VERSION 5.7 ;
  NOWIREEXTENSIONATPIN ON ;
  DIVIDERCHAR "/" ;
  BUSBITCHARS "[]" ;
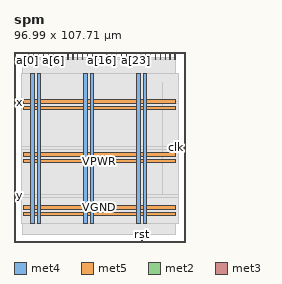
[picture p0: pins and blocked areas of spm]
MACRO spm
  CLASS BLOCK ;
  FOREIGN spm ;
  ORIGIN 0.000 0.000 ;
  SIZE 96.990 BY 107.710 ;
  PIN VGND
    DIRECTION INOUT ;
    USE GROUND ;
    PORT
      LAYER met4 ;
        RECT 13.220 10.640 15.220 95.440 ;
    END
    PORT
      LAYER met4 ;
        RECT 43.220 10.640 45.220 95.440 ;
    END
    PORT
      LAYER met4 ;
        RECT 73.220 10.640 75.220 95.440 ;
    END
    PORT
      LAYER met5 ;
        RECT 5.280 18.580 91.320 20.580 ;
    END
    PORT
      LAYER met5 ;
        RECT 5.280 48.580 91.320 50.580 ;
    END
    PORT
      LAYER met5 ;
        RECT 5.280 78.580 91.320 80.580 ;
    END
  END VGND
  PIN VPWR
    DIRECTION INOUT ;
    USE POWER ;
    PORT
      LAYER met4 ;
        RECT 9.520 10.640 11.520 95.440 ;
    END
    PORT
      LAYER met4 ;
        RECT 39.520 10.640 41.520 95.440 ;
    END
    PORT
      LAYER met4 ;
        RECT 69.520 10.640 71.520 95.440 ;
    END
    PORT
      LAYER met5 ;
        RECT 5.280 14.880 91.320 16.880 ;
    END
    PORT
      LAYER met5 ;
        RECT 5.280 44.880 91.320 46.880 ;
    END
    PORT
      LAYER met5 ;
        RECT 5.280 74.880 91.320 76.880 ;
    END
  END VPWR
  PIN a[0]
    DIRECTION INPUT ;
    USE SIGNAL ;
    ANTENNAGATEAREA 0.196500 ;
    PORT
      LAYER met2 ;
        RECT 5.610 103.710 5.890 107.710 ;
    END
  END a[0]
  PIN a[10]
    DIRECTION INPUT ;
    USE SIGNAL ;
    ANTENNAGATEAREA 0.196500 ;
    PORT
      LAYER met2 ;
        RECT 33.210 103.710 33.490 107.710 ;
    END
  END a[10]
  PIN a[11]
    DIRECTION INPUT ;
    USE SIGNAL ;
    ANTENNAGATEAREA 0.196500 ;
    PORT
      LAYER met2 ;
        RECT 35.970 103.710 36.250 107.710 ;
    END
  END a[11]
  PIN a[12]
    DIRECTION INPUT ;
    USE SIGNAL ;
    ANTENNAGATEAREA 0.196500 ;
    PORT
      LAYER met2 ;
        RECT 38.730 103.710 39.010 107.710 ;
    END
  END a[12]
  PIN a[13]
    DIRECTION INPUT ;
    USE SIGNAL ;
    ANTENNAGATEAREA 0.196500 ;
    PORT
      LAYER met2 ;
        RECT 41.490 103.710 41.770 107.710 ;
    END
  END a[13]
  PIN a[14]
    DIRECTION INPUT ;
    USE SIGNAL ;
    ANTENNAGATEAREA 0.196500 ;
    PORT
      LAYER met2 ;
        RECT 44.250 103.710 44.530 107.710 ;
    END
  END a[14]
  PIN a[15]
    DIRECTION INPUT ;
    USE SIGNAL ;
    ANTENNAGATEAREA 0.196500 ;
    PORT
      LAYER met2 ;
        RECT 47.010 103.710 47.290 107.710 ;
    END
  END a[15]
  PIN a[16]
    DIRECTION INPUT ;
    USE SIGNAL ;
    ANTENNAGATEAREA 0.196500 ;
    PORT
      LAYER met2 ;
        RECT 49.770 103.710 50.050 107.710 ;
    END
  END a[16]
  PIN a[17]
    DIRECTION INPUT ;
    USE SIGNAL ;
    ANTENNAGATEAREA 0.196500 ;
    PORT
      LAYER met2 ;
        RECT 52.530 103.710 52.810 107.710 ;
    END
  END a[17]
  PIN a[18]
    DIRECTION INPUT ;
    USE SIGNAL ;
    ANTENNAGATEAREA 0.196500 ;
    PORT
      LAYER met2 ;
        RECT 55.290 103.710 55.570 107.710 ;
    END
  END a[18]
  PIN a[19]
    DIRECTION INPUT ;
    USE SIGNAL ;
    ANTENNAGATEAREA 0.196500 ;
    PORT
      LAYER met2 ;
        RECT 58.050 103.710 58.330 107.710 ;
    END
  END a[19]
  PIN a[1]
    DIRECTION INPUT ;
    USE SIGNAL ;
    ANTENNAGATEAREA 0.196500 ;
    PORT
      LAYER met2 ;
        RECT 8.370 103.710 8.650 107.710 ;
    END
  END a[1]
  PIN a[20]
    DIRECTION INPUT ;
    USE SIGNAL ;
    ANTENNAGATEAREA 0.196500 ;
    PORT
      LAYER met2 ;
        RECT 60.810 103.710 61.090 107.710 ;
    END
  END a[20]
  PIN a[21]
    DIRECTION INPUT ;
    USE SIGNAL ;
    ANTENNAGATEAREA 0.196500 ;
    PORT
      LAYER met2 ;
        RECT 63.570 103.710 63.850 107.710 ;
    END
  END a[21]
  PIN a[22]
    DIRECTION INPUT ;
    USE SIGNAL ;
    ANTENNAGATEAREA 0.196500 ;
    PORT
      LAYER met2 ;
        RECT 66.330 103.710 66.610 107.710 ;
    END
  END a[22]
  PIN a[23]
    DIRECTION INPUT ;
    USE SIGNAL ;
    ANTENNAGATEAREA 0.196500 ;
    PORT
      LAYER met2 ;
        RECT 69.090 103.710 69.370 107.710 ;
    END
  END a[23]
  PIN a[24]
    DIRECTION INPUT ;
    USE SIGNAL ;
    ANTENNAGATEAREA 0.196500 ;
    PORT
      LAYER met2 ;
        RECT 71.850 103.710 72.130 107.710 ;
    END
  END a[24]
  PIN a[25]
    DIRECTION INPUT ;
    USE SIGNAL ;
    ANTENNAGATEAREA 0.196500 ;
    PORT
      LAYER met2 ;
        RECT 74.610 103.710 74.890 107.710 ;
    END
  END a[25]
  PIN a[26]
    DIRECTION INPUT ;
    USE SIGNAL ;
    ANTENNAGATEAREA 0.196500 ;
    PORT
      LAYER met2 ;
        RECT 77.370 103.710 77.650 107.710 ;
    END
  END a[26]
  PIN a[27]
    DIRECTION INPUT ;
    USE SIGNAL ;
    ANTENNAGATEAREA 0.196500 ;
    PORT
      LAYER met2 ;
        RECT 80.130 103.710 80.410 107.710 ;
    END
  END a[27]
  PIN a[28]
    DIRECTION INPUT ;
    USE SIGNAL ;
    ANTENNAGATEAREA 0.196500 ;
    PORT
      LAYER met2 ;
        RECT 82.890 103.710 83.170 107.710 ;
    END
  END a[28]
  PIN a[29]
    DIRECTION INPUT ;
    USE SIGNAL ;
    ANTENNAGATEAREA 0.196500 ;
    PORT
      LAYER met2 ;
        RECT 85.650 103.710 85.930 107.710 ;
    END
  END a[29]
  PIN a[2]
    DIRECTION INPUT ;
    USE SIGNAL ;
    ANTENNAGATEAREA 0.196500 ;
    PORT
      LAYER met2 ;
        RECT 11.130 103.710 11.410 107.710 ;
    END
  END a[2]
  PIN a[30]
    DIRECTION INPUT ;
    USE SIGNAL ;
    ANTENNAGATEAREA 0.196500 ;
    PORT
      LAYER met2 ;
        RECT 88.410 103.710 88.690 107.710 ;
    END
  END a[30]
  PIN a[31]
    DIRECTION INPUT ;
    USE SIGNAL ;
    ANTENNAGATEAREA 0.196500 ;
    PORT
      LAYER met2 ;
        RECT 91.170 103.710 91.450 107.710 ;
    END
  END a[31]
  PIN a[3]
    DIRECTION INPUT ;
    USE SIGNAL ;
    ANTENNAGATEAREA 0.196500 ;
    PORT
      LAYER met2 ;
        RECT 13.890 103.710 14.170 107.710 ;
    END
  END a[3]
  PIN a[4]
    DIRECTION INPUT ;
    USE SIGNAL ;
    ANTENNAGATEAREA 0.196500 ;
    PORT
      LAYER met2 ;
        RECT 16.650 103.710 16.930 107.710 ;
    END
  END a[4]
  PIN a[5]
    DIRECTION INPUT ;
    USE SIGNAL ;
    ANTENNAGATEAREA 0.196500 ;
    PORT
      LAYER met2 ;
        RECT 19.410 103.710 19.690 107.710 ;
    END
  END a[5]
  PIN a[6]
    DIRECTION INPUT ;
    USE SIGNAL ;
    ANTENNAGATEAREA 0.196500 ;
    PORT
      LAYER met2 ;
        RECT 22.170 103.710 22.450 107.710 ;
    END
  END a[6]
  PIN a[7]
    DIRECTION INPUT ;
    USE SIGNAL ;
    ANTENNAGATEAREA 0.196500 ;
    PORT
      LAYER met2 ;
        RECT 24.930 103.710 25.210 107.710 ;
    END
  END a[7]
  PIN a[8]
    DIRECTION INPUT ;
    USE SIGNAL ;
    ANTENNAGATEAREA 0.196500 ;
    PORT
      LAYER met2 ;
        RECT 27.690 103.710 27.970 107.710 ;
    END
  END a[8]
  PIN a[9]
    DIRECTION INPUT ;
    USE SIGNAL ;
    ANTENNAGATEAREA 0.196500 ;
    PORT
      LAYER met2 ;
        RECT 30.450 103.710 30.730 107.710 ;
    END
  END a[9]
  PIN clk
    DIRECTION INPUT ;
    USE SIGNAL ;
    ANTENNAGATEAREA 0.852000 ;
    PORT
      LAYER met3 ;
        RECT 92.990 53.080 96.990 53.680 ;
    END
  END clk
  PIN rst
    DIRECTION INPUT ;
    USE SIGNAL ;
    ANTENNAGATEAREA 0.990000 ;
    PORT
      LAYER met2 ;
        RECT 72.310 0.000 72.590 4.000 ;
    END
  END rst
  PIN x
    DIRECTION INPUT ;
    USE SIGNAL ;
    ANTENNAGATEAREA 0.196500 ;
    PORT
      LAYER met3 ;
        RECT 0.000 78.920 4.000 79.520 ;
    END
  END x
  PIN y
    DIRECTION OUTPUT TRISTATE ;
    USE SIGNAL ;
    ANTENNADIFFAREA 0.340600 ;
    PORT
      LAYER met3 ;
        RECT 0.000 25.880 4.000 26.480 ;
    END
  END y
  OBS
      LAYER li1 ;
        RECT 5.520 10.795 91.080 95.285 ;
      LAYER met1 ;
        RECT 4.670 10.640 91.470 95.840 ;
      LAYER met2 ;
        RECT 4.690 103.430 5.330 104.450 ;
        RECT 6.170 103.430 8.090 104.450 ;
        RECT 8.930 103.430 10.850 104.450 ;
        RECT 11.690 103.430 13.610 104.450 ;
        RECT 14.450 103.430 16.370 104.450 ;
        RECT 17.210 103.430 19.130 104.450 ;
        RECT 19.970 103.430 21.890 104.450 ;
        RECT 22.730 103.430 24.650 104.450 ;
        RECT 25.490 103.430 27.410 104.450 ;
        RECT 28.250 103.430 30.170 104.450 ;
        RECT 31.010 103.430 32.930 104.450 ;
        RECT 33.770 103.430 35.690 104.450 ;
        RECT 36.530 103.430 38.450 104.450 ;
        RECT 39.290 103.430 41.210 104.450 ;
        RECT 42.050 103.430 43.970 104.450 ;
        RECT 44.810 103.430 46.730 104.450 ;
        RECT 47.570 103.430 49.490 104.450 ;
        RECT 50.330 103.430 52.250 104.450 ;
        RECT 53.090 103.430 55.010 104.450 ;
        RECT 55.850 103.430 57.770 104.450 ;
        RECT 58.610 103.430 60.530 104.450 ;
        RECT 61.370 103.430 63.290 104.450 ;
        RECT 64.130 103.430 66.050 104.450 ;
        RECT 66.890 103.430 68.810 104.450 ;
        RECT 69.650 103.430 71.570 104.450 ;
        RECT 72.410 103.430 74.330 104.450 ;
        RECT 75.170 103.430 77.090 104.450 ;
        RECT 77.930 103.430 79.850 104.450 ;
        RECT 80.690 103.430 82.610 104.450 ;
        RECT 83.450 103.430 85.370 104.450 ;
        RECT 86.210 103.430 88.130 104.450 ;
        RECT 88.970 103.430 90.890 104.450 ;
        RECT 4.690 4.280 91.440 103.430 ;
        RECT 4.690 4.000 72.030 4.280 ;
        RECT 72.870 4.000 91.440 4.280 ;
      LAYER met3 ;
        RECT 3.990 79.920 92.990 95.365 ;
        RECT 4.400 78.520 92.990 79.920 ;
        RECT 3.990 54.080 92.990 78.520 ;
        RECT 3.990 52.680 92.590 54.080 ;
        RECT 3.990 26.880 92.990 52.680 ;
        RECT 4.400 25.480 92.990 26.880 ;
        RECT 3.990 10.715 92.990 25.480 ;
      LAYER met4 ;
        RECT 84.015 27.375 84.345 90.265 ;
  END
END spm
END LIBRARY

